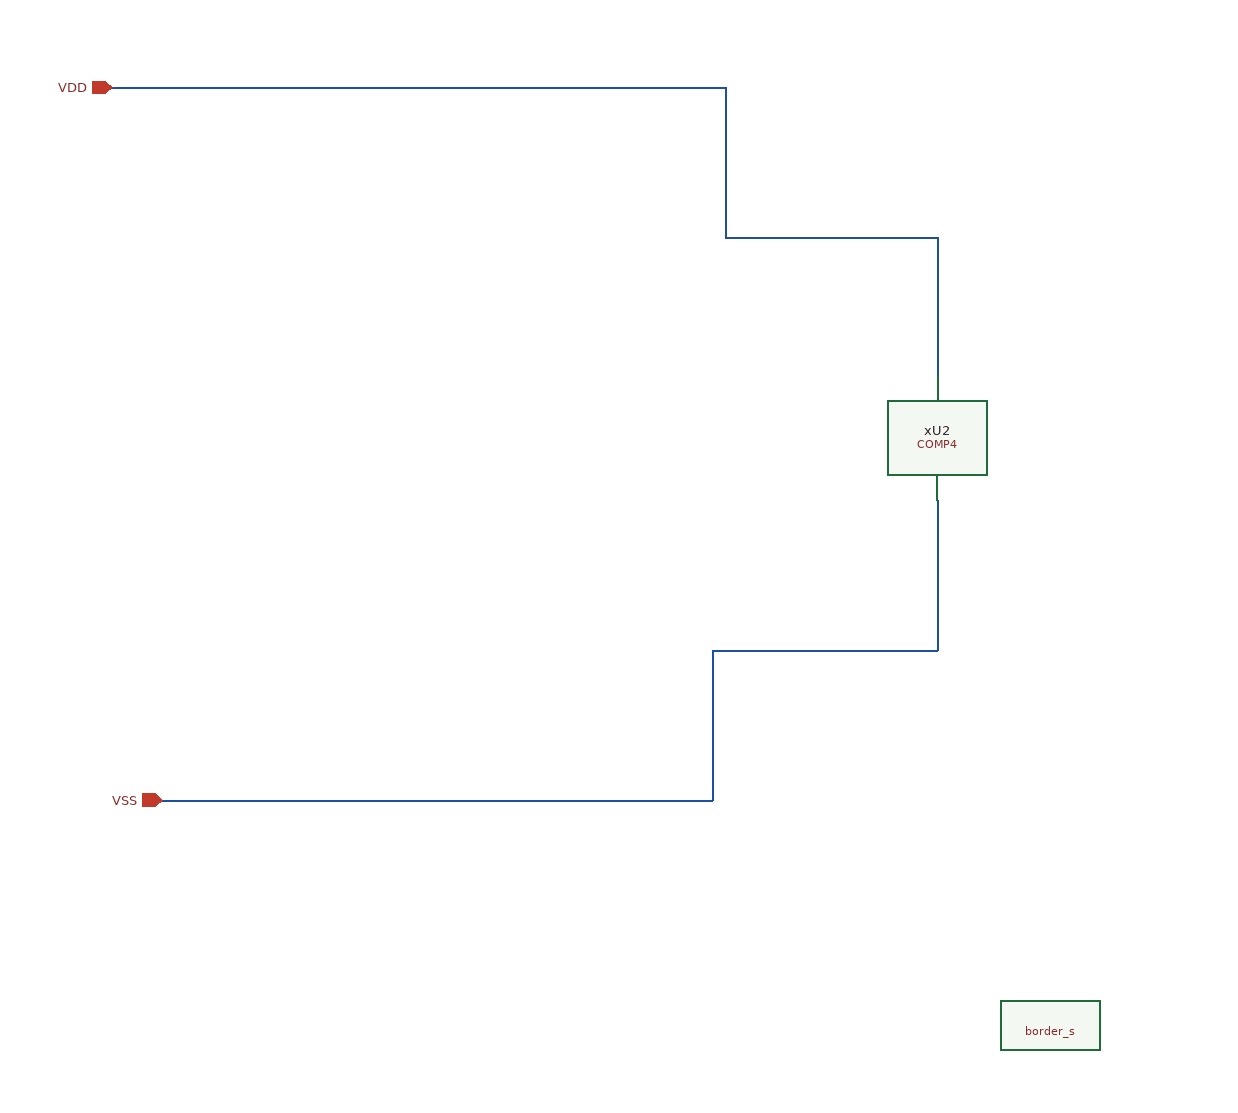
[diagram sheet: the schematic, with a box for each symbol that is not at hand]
v {xschem version=3.4.6 file_version=1.2}
G {}
K {}
V {}
S {}
E {}
N 740 -880 1230 -880 {lab=VDD}
N 780 -310 1020 -310 {lab=VSS}
N 1220 -430 1390 -430 {lab=VSS}
N 1020 -310 1220 -310 {
lab=VSS}
N 1220 -430 1220 -310 {
lab=VSS}
N 1230 -880 1230 -760 {
lab=VDD}
N 1230 -760 1390 -760 {
lab=VDD}
N 1390 -760 1400 -760 {lab=VDD}
N 1400 -470 1400 -430 {lab=VSS}
N 1390 -430 1400 -430 {lab=VSS}
N 1400 -760 1400 -720 {lab=VDD}
N 1400 -510 1400 -470 {lab=VSS}
N 1400 -720 1400 -650 {lab=VDD}
N 1400 -550 1400 -510 {lab=VSS}
C {cborder/border_s.sym} 1490 -130 0 0 {
user="bkle"
company="bkle"}
C {devices/ipin.sym} 740 -880 0 0 {name=p3 lab=VDD}
C {devices/ipin.sym} 780 -310 0 0 {name=p5 lab=VSS}
C {JNW_BKLE_SKY130A/COMP4.sym} 1290 -700 0 0 {name=xU2}
